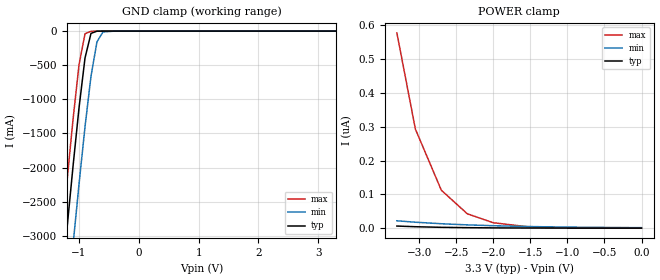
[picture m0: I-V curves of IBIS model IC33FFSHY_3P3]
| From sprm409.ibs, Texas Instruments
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|   Model IC33FFSHY_3P3
[Model]   IC33FFSHY_3P3
Model_type   Input
Polarity   Non-Inverting
Vinl =   0.9900V
Vinh =   2.3100V
C_comp   2.1548pF   2.3140pF   2.1455pF
[Temperature Range]   25.0000   0.1250k   -40.0000
[Voltage Range]   3.3000V   3.0000V   3.6000V
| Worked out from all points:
|   GND clamp passes 1 mA (typ) near -0.69 V on its own axis
[GND_clamp]
| voltage   I(typ)   I(min)   I(max)
-3.3V     -23.34A    -24.42A    -22.71A
-1.3V     -3.808A    -4.968A    -3.114A
-1.2V     -2.88A     -4.039A    -2.185A
-1.1V     -1.977A    -3.127A    -1.292A
-1V       -1.123A    -2.241A    -489.8mA
-900mV    -393.5mA   -1.402A    -39.28mA
-800mV    -34.06mA   -660.7mA   -2.403mA
-700mV    -1.064mA   -156.4mA   -232.2uA
-600mV    -42.88uA   -13.11mA   -13.27uA
-400mV    -95.53nA   -45.69uA   -11.78nA
3.3V      208.1pA    2.034nA    195.9pA
[POWER_clamp]
| voltage   I(typ)   I(min)   I(max)
-3.3V     6.476nA    22.01nA    577.7nA
-3.05V    4.458nA    17.81nA    293nA
-2.7V     2.682nA    13.27nA    112.3nA
-2.35V    1.654nA    9.906nA    42.75nA
-2V       1.057nA    7.425nA    16.25nA
-1.55V    638.1pA    5.165nA    4.761nA
-1.5V     606.7pA    4.964nA    4.166nA
-1.35V    524.9pA    4.411nA    2.81nA
-1.25V    479.5pA    4.081nA    2.176nA
-1V       389.9pA    3.37nA     1.189nA
-600mV    295.6pA    2.51nA     529.7pA
0V        208.1pA    1.655nA    247.7pA
